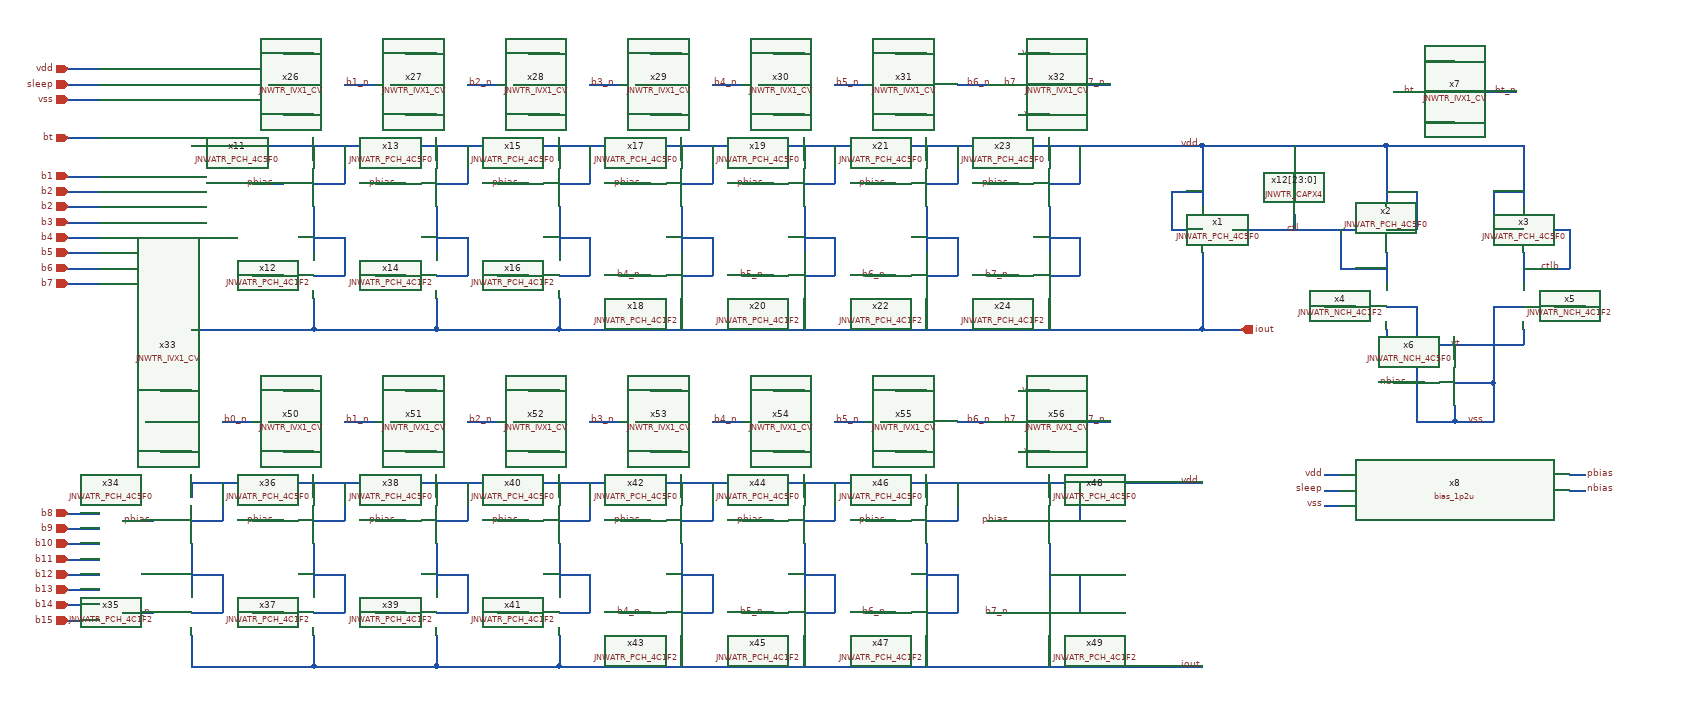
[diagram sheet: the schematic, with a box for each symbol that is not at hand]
v {xschem version=3.4.6 file_version=1.2}
G {}
K {}
V {}
S {}
E {}
N 920 330 960 330 {lab=pbias}
N 1000 280 1000 300 {lab=vdd}
N 1000 360 1000 420 {lab=#net1}
N 1000 480 1000 520 {lab=iout}
N 920 450 960 450 {lab=b4_n}
N 1000 330 1040 330 {lab=vdd}
N 1040 280 1040 330 {lab=vdd}
N 1000 450 1040 450 {lab=#net1}
N 1040 400 1040 450 {lab=#net1}
N 1000 400 1040 400 {lab=#net1}
N 1020 520 1180 520 {lab=iout}
N 1080 330 1120 330 {lab=pbias}
N 1160 280 1160 300 {lab=vdd}
N 1160 360 1160 420 {lab=#net2}
N 1160 480 1160 520 {lab=iout}
N 1080 450 1120 450 {lab=b5_n}
N 1160 330 1200 330 {lab=vdd}
N 1200 280 1200 330 {lab=vdd}
N 1160 450 1200 450 {lab=#net2}
N 1200 400 1200 450 {lab=#net2}
N 1160 400 1200 400 {lab=#net2}
N 1180 520 1340 520 {lab=iout}
N 1240 330 1280 330 {lab=pbias}
N 1320 280 1320 300 {lab=vdd}
N 1320 360 1320 420 {lab=#net3}
N 1320 480 1320 520 {lab=iout}
N 1240 450 1280 450 {lab=b6_n}
N 1320 330 1360 330 {lab=vdd}
N 1360 280 1360 330 {lab=vdd}
N 1320 450 1360 450 {lab=#net3}
N 1360 400 1360 450 {lab=#net3}
N 1320 400 1360 400 {lab=#net3}
N 1340 520 1500 520 {lab=iout}
N 1400 330 1440 330 {lab=pbias}
N 1480 280 1480 300 {lab=vdd}
N 1480 360 1480 420 {lab=#net4}
N 1480 480 1480 520 {lab=iout}
N 1400 450 1440 450 {lab=b7_n}
N 1480 330 1520 330 {lab=vdd}
N 1520 280 1520 330 {lab=vdd}
N 1480 450 1520 450 {lab=#net4}
N 1520 400 1520 450 {lab=#net4}
N 1480 400 1520 400 {lab=#net4}
N 1020 280 1680 280 {lab=vdd}
N 200 340 240 340 {lab=b2}
N 200 360 240 360 {lab=b2}
N 200 380 240 380 {lab=b3}
N 200 400 240 400 {lab=b4}
N 460 200 480 200 {lab=b1}
N 480 160 520 160 {lab=vdd}
N 480 240 520 240 {lab=vss}
N 560 200 600 200 {lab=b1_n}
N 620 200 640 200 {lab=b2}
N 640 160 680 160 {lab=vdd}
N 640 240 680 240 {lab=vss}
N 720 200 760 200 {lab=b2_n}
N 780 200 800 200 {lab=b3}
N 800 160 840 160 {lab=vdd}
N 800 240 840 240 {lab=vss}
N 880 200 920 200 {lab=b3_n}
N 940 200 960 200 {lab=b4}
N 960 160 1000 160 {lab=vdd}
N 960 240 1000 240 {lab=vss}
N 1040 200 1080 200 {lab=b4_n}
N 1840 730 1860 730 {lab=sleep}
N 2160 730 2180 730 {lab=nbias}
N 2160 710 2180 710 {lab=pbias}
N 1840 750 1860 750 {lab=vss}
N 1840 710 1860 710 {lab=vdd}
N 1720 390 1880 390 {lab=ctl}
N 1680 280 1680 360 {lab=vdd}
N 1500 520 1680 520 {lab=iout}
N 1800 370 1800 390 {lab=ctl}
N 1800 280 1800 300 {lab=vdd}
N 1680 280 1920 280 {lab=vdd}
N 1920 280 1920 360 {lab=vdd}
N 1920 390 1960 390 {lab=vdd}
N 1960 340 1960 390 {lab=vdd}
N 1920 340 1960 340 {lab=vdd}
N 1860 390 1860 440 {lab=ctl}
N 1860 440 1920 440 {lab=ctl}
N 1920 420 1920 460 {lab=ctl}
N 2140 390 2160 390 {lab=ctlb}
N 2100 280 2100 360 {lab=vdd}
N 2060 390 2100 390 {lab=vdd}
N 2060 340 2060 390 {lab=vdd}
N 2160 390 2160 440 {lab=ctlb}
N 2100 440 2160 440 {lab=ctlb}
N 2100 420 2100 460 {lab=ctlb}
N 1920 280 2100 280 {lab=vdd}
N 2060 340 2100 340 {lab=vdd}
N 1680 420 1680 520 {lab=iout}
N 2060 490 2100 490 {lab=vss}
N 1920 490 1960 490 {lab=vss}
N 1920 520 1920 540 {lab=vt}
N 2100 520 2100 540 {lab=vt}
N 1840 490 1880 490 {lab=bt}
N 2140 490 2180 490 {lab=bt_n}
N 2010 540 2010 560 {lab=vt}
N 2060 590 2060 640 {lab=vss}
N 1640 390 1680 390 {lab=vdd}
N 1640 340 1640 390 {lab=vdd}
N 1640 340 1680 340 {lab=vdd}
N 2010 620 2010 640 {lab=vss}
N 2010 590 2060 590 {lab=vss}
N 2010 640 2060 640 {lab=vss}
N 1930 590 1970 590 {lab=nbias}
N 1680 520 1730 520 {lab=iout}
N 200 200 240 200 {lab=sleep}
N 200 180 240 180 {lab=vdd}
N 200 220 240 220 {lab=vss}
N 360 520 520 520 {lab=iout}
N 440 330 480 330 {lab=pbias}
N 520 280 520 300 {lab=vdd}
N 520 360 520 420 {lab=#net5}
N 520 480 520 520 {lab=iout}
N 440 450 480 450 {lab=b1_n}
N 520 330 560 330 {lab=vdd}
N 560 280 560 330 {lab=vdd}
N 520 450 560 450 {lab=#net5}
N 560 400 560 450 {lab=#net5}
N 520 400 560 400 {lab=#net5}
N 520 520 680 520 {lab=iout}
N 600 330 640 330 {lab=pbias}
N 680 280 680 300 {lab=vdd}
N 680 360 680 420 {lab=#net6}
N 680 480 680 520 {lab=iout}
N 600 450 640 450 {lab=b2_n}
N 680 330 720 330 {lab=vdd}
N 720 280 720 330 {lab=vdd}
N 680 450 720 450 {lab=#net6}
N 720 400 720 450 {lab=#net6}
N 680 400 720 400 {lab=#net6}
N 680 520 840 520 {lab=iout}
N 760 330 800 330 {lab=pbias}
N 840 280 840 300 {lab=vdd}
N 840 360 840 420 {lab=#net7}
N 840 480 840 520 {lab=iout}
N 760 450 800 450 {lab=b3_n}
N 840 330 880 330 {lab=vdd}
N 880 280 880 330 {lab=vdd}
N 840 450 880 450 {lab=#net7}
N 880 400 880 450 {lab=#net7}
N 840 400 880 400 {lab=#net7}
N 360 280 1020 280 {lab=vdd}
N 840 520 1020 520 {lab=iout}
N 200 420 240 420 {lab=b5}
N 200 440 240 440 {lab=b6}
N 200 460 240 460 {lab=b7}
N 1100 200 1120 200 {lab=b5}
N 1120 160 1160 160 {lab=vdd}
N 1120 240 1160 240 {lab=vss}
N 1200 200 1240 200 {lab=b5_n}
N 1260 200 1280 200 {lab=b6}
N 1280 160 1320 160 {lab=vdd}
N 1280 240 1320 240 {lab=vss}
N 1360 200 1400 200 {lab=b6_n}
N 1420 200 1440 200 {lab=b7}
N 1440 160 1480 160 {lab=vdd}
N 1440 240 1480 240 {lab=vss}
N 1520 200 1560 200 {lab=b7_n}
N 1930 210 1970 210 {lab=bt}
N 1970 170 2010 170 {lab=vdd}
N 1970 250 2010 250 {lab=vss}
N 2050 210 2090 210 {lab=bt_n}
N 200 270 240 270 {lab=bt}
N 200 780 240 780 {lab=b9}
N 200 800 240 800 {lab=b10}
N 200 820 240 820 {lab=b11}
N 200 840 240 840 {lab=b12}
N 200 760 240 760 {lab=b8}
N 200 860 240 860 {lab=b13}
N 200 880 240 880 {lab=b14}
N 200 900 240 900 {lab=b15}
N 1960 490 1960 640 {lab=vss}
N 1960 640 2010 640 {lab=vss}
N 2060 490 2060 590 {lab=vss}
N 1920 540 2100 540 {lab=vt}
N 920 770 960 770 {lab=pbias}
N 1000 720 1000 740 {lab=vdd}
N 1000 800 1000 860 {lab=#net8}
N 1000 920 1000 960 {lab=iout}
N 920 890 960 890 {lab=b4_n}
N 1000 770 1040 770 {lab=vdd}
N 1040 720 1040 770 {lab=vdd}
N 1000 890 1040 890 {lab=#net8}
N 1040 840 1040 890 {lab=#net8}
N 1000 840 1040 840 {lab=#net8}
N 1020 960 1180 960 {lab=iout}
N 1080 770 1120 770 {lab=pbias}
N 1160 720 1160 740 {lab=vdd}
N 1160 800 1160 860 {lab=#net9}
N 1160 920 1160 960 {lab=iout}
N 1080 890 1120 890 {lab=b5_n}
N 1160 770 1200 770 {lab=vdd}
N 1200 720 1200 770 {lab=vdd}
N 1160 890 1200 890 {lab=#net9}
N 1200 840 1200 890 {lab=#net9}
N 1160 840 1200 840 {lab=#net9}
N 1180 960 1340 960 {lab=iout}
N 1240 770 1280 770 {lab=pbias}
N 1320 720 1320 740 {lab=vdd}
N 1320 800 1320 860 {lab=#net10}
N 1320 920 1320 960 {lab=iout}
N 1240 890 1280 890 {lab=b6_n}
N 1320 770 1360 770 {lab=vdd}
N 1360 720 1360 770 {lab=vdd}
N 1320 890 1360 890 {lab=#net10}
N 1360 840 1360 890 {lab=#net10}
N 1320 840 1360 840 {lab=#net10}
N 1340 960 1500 960 {lab=iout}
N 1400 770 1440 770 {lab=pbias}
N 1480 720 1480 740 {lab=vdd}
N 1480 800 1480 860 {lab=#net11}
N 1480 920 1480 960 {lab=iout}
N 1400 890 1440 890 {lab=b7_n}
N 1480 770 1520 770 {lab=vdd}
N 1520 720 1520 770 {lab=vdd}
N 1480 890 1520 890 {lab=#net11}
N 1520 840 1520 890 {lab=#net11}
N 1480 840 1520 840 {lab=#net11}
N 1020 720 1680 720 {lab=vdd}
N 300 640 320 640 {lab=b0}
N 320 600 360 600 {lab=vdd}
N 320 680 360 680 {lab=vss}
N 400 640 440 640 {lab=b0_n}
N 460 640 480 640 {lab=b1}
N 480 600 520 600 {lab=vdd}
N 480 680 520 680 {lab=vss}
N 560 640 600 640 {lab=b1_n}
N 620 640 640 640 {lab=b2}
N 640 600 680 600 {lab=vdd}
N 640 680 680 680 {lab=vss}
N 720 640 760 640 {lab=b2_n}
N 780 640 800 640 {lab=b3}
N 800 600 840 600 {lab=vdd}
N 800 680 840 680 {lab=vss}
N 880 640 920 640 {lab=b3_n}
N 940 640 960 640 {lab=b4}
N 960 600 1000 600 {lab=vdd}
N 960 680 1000 680 {lab=vss}
N 1040 640 1080 640 {lab=b4_n}
N 1500 960 1680 960 {lab=iout}
N 270 770 310 770 {lab=pbias}
N 360 720 360 740 {lab=vdd}
N 360 800 360 860 {lab=#net12}
N 360 920 360 960 {lab=iout}
N 270 890 310 890 {lab=b0_n}
N 360 770 400 770 {lab=vdd}
N 400 720 400 770 {lab=vdd}
N 360 890 400 890 {lab=#net12}
N 400 840 400 890 {lab=#net12}
N 360 840 400 840 {lab=#net12}
N 360 960 520 960 {lab=iout}
N 440 770 480 770 {lab=pbias}
N 520 720 520 740 {lab=vdd}
N 520 800 520 860 {lab=#net13}
N 520 920 520 960 {lab=iout}
N 440 890 480 890 {lab=b1_n}
N 520 770 560 770 {lab=vdd}
N 560 720 560 770 {lab=vdd}
N 520 890 560 890 {lab=#net13}
N 560 840 560 890 {lab=#net13}
N 520 840 560 840 {lab=#net13}
N 520 960 680 960 {lab=iout}
N 600 770 640 770 {lab=pbias}
N 680 720 680 740 {lab=vdd}
N 680 800 680 860 {lab=#net14}
N 680 920 680 960 {lab=iout}
N 600 890 640 890 {lab=b2_n}
N 680 770 720 770 {lab=vdd}
N 720 720 720 770 {lab=vdd}
N 680 890 720 890 {lab=#net14}
N 720 840 720 890 {lab=#net14}
N 680 840 720 840 {lab=#net14}
N 680 960 840 960 {lab=iout}
N 760 770 800 770 {lab=pbias}
N 840 720 840 740 {lab=vdd}
N 840 800 840 860 {lab=#net15}
N 840 920 840 960 {lab=iout}
N 760 890 800 890 {lab=b3_n}
N 840 770 880 770 {lab=vdd}
N 880 720 880 770 {lab=vdd}
N 840 890 880 890 {lab=#net15}
N 880 840 880 890 {lab=#net15}
N 840 840 880 840 {lab=#net15}
N 360 720 1020 720 {lab=vdd}
N 840 960 1020 960 {lab=iout}
N 1100 640 1120 640 {lab=b5}
N 1120 600 1160 600 {lab=vdd}
N 1120 680 1160 680 {lab=vss}
N 1200 640 1240 640 {lab=b5_n}
N 1260 640 1280 640 {lab=b6}
N 1280 600 1320 600 {lab=vdd}
N 1280 680 1320 680 {lab=vss}
N 1360 640 1400 640 {lab=b6_n}
N 1420 640 1440 640 {lab=b7}
N 1440 600 1480 600 {lab=vdd}
N 1440 680 1480 680 {lab=vss}
N 1520 640 1560 640 {lab=b7_n}
N 200 320 240 320 {lab=b1}
C {devices/lab_wire.sym} 1430 450 0 0 {name=p3 sig_type=std_logic lab=b7_n
}
C {devices/lab_wire.sym} 1270 450 0 0 {name=p4 sig_type=std_logic lab=b6_n
}
C {devices/lab_wire.sym} 1110 450 0 0 {name=p5 sig_type=std_logic lab=b5_n
}
C {devices/lab_wire.sym} 950 450 0 0 {name=p6 sig_type=std_logic lab=b4_n
}
C {devices/ipin.sym} 200 180 0 0 {name=p14 lab=vdd}
C {devices/ipin.sym} 200 220 0 0 {name=p15 lab=vss}
C {devices/ipin.sym} 200 340 0 0 {name=p17 lab=b2}
C {devices/ipin.sym} 200 360 0 0 {name=p18 lab=b2}
C {devices/ipin.sym} 200 380 0 0 {name=p19 lab=b3}
C {devices/ipin.sym} 200 400 0 0 {name=p20 lab=b4}
C {devices/lab_wire.sym} 510 240 2 1 {name=p26 sig_type=std_logic lab=vss}
C {devices/lab_wire.sym} 510 160 0 0 {name=p27 sig_type=std_logic lab=vdd}
C {devices/lab_wire.sym} 670 240 2 1 {name=p30 sig_type=std_logic lab=vss}
C {devices/lab_wire.sym} 670 160 0 0 {name=p31 sig_type=std_logic lab=vdd}
C {devices/lab_wire.sym} 830 240 2 1 {name=p34 sig_type=std_logic lab=vss}
C {devices/lab_wire.sym} 830 160 0 0 {name=p35 sig_type=std_logic lab=vdd}
C {devices/lab_wire.sym} 990 240 2 1 {name=p38 sig_type=std_logic lab=vss}
C {devices/lab_wire.sym} 990 160 0 0 {name=p39 sig_type=std_logic lab=vdd}
C {devices/lab_wire.sym} 800 200 0 0 {name=p25 sig_type=std_logic lab=b3}
C {devices/lab_wire.sym} 480 200 0 0 {name=p28 sig_type=std_logic lab=b1}
C {devices/lab_wire.sym} 960 200 0 0 {name=p29 sig_type=std_logic lab=b4}
C {devices/lab_wire.sym} 640 200 0 0 {name=p32 sig_type=std_logic lab=b2}
C {devices/lab_wire.sym} 880 200 0 1 {name=p36 sig_type=std_logic lab=b3_n}
C {devices/lab_wire.sym} 560 200 0 1 {name=p40 sig_type=std_logic lab=b1_n}
C {devices/lab_wire.sym} 1040 200 0 1 {name=p41 sig_type=std_logic lab=b4_n}
C {devices/lab_wire.sym} 720 200 0 1 {name=p45 sig_type=std_logic lab=b2_n}
C {devices/lab_wire.sym} 1110 330 0 0 {name=p9 sig_type=std_logic lab=pbias
}
C {devices/lab_wire.sym} 1270 330 0 0 {name=p8 sig_type=std_logic lab=pbias
}
C {devices/lab_wire.sym} 1430 330 0 0 {name=p10 sig_type=std_logic lab=pbias
}
C {devices/lab_wire.sym} 950 330 0 0 {name=p12 sig_type=std_logic lab=pbias
}
C {devices/ipin.sym} 200 200 0 0 {name=p33 lab=sleep}
C {devices/lab_wire.sym} 2180 710 0 1 {name=p13 sig_type=std_logic lab=pbias
}
C {devices/lab_wire.sym} 2180 730 0 1 {name=p21 sig_type=std_logic lab=nbias
}
C {JNW_TR_SKY130A/JNWTR_CAPX4.sym} 1800 360 0 0 {name=x12[23:0]}
C {devices/lab_wire.sym} 2150 490 0 1 {name=p1 sig_type=std_logic lab=bt_n}
C {devices/lab_wire.sym} 1870 490 0 0 {name=p2 sig_type=std_logic lab=bt}
C {devices/lab_wire.sym} 1950 590 0 0 {name=p11 sig_type=std_logic lab=nbias
}
C {devices/lab_wire.sym} 1810 390 2 1 {name=p42 sig_type=std_logic lab=ctl
}
C {devices/lab_wire.sym} 2120 440 2 0 {name=p43 sig_type=std_logic lab=ctlb
}
C {devices/lab_wire.sym} 2020 540 0 0 {name=p44 sig_type=std_logic lab=vt}
C {devices/lab_wire.sym} 1840 750 0 0 {name=p50 sig_type=std_logic lab=vss
}
C {devices/lab_wire.sym} 1840 710 0 0 {name=p51 sig_type=std_logic lab=vdd
}
C {devices/opin.sym} 1730 520 0 0 {name=p54 lab=iout}
C {devices/lab_wire.sym} 2050 640 0 0 {name=p52 sig_type=std_logic lab=vss
}
C {devices/lab_wire.sym} 1840 730 0 0 {name=p53 sig_type=std_logic lab=sleep
}
C {devices/lab_wire.sym} 790 450 0 0 {name=p55 sig_type=std_logic lab=b3_n
}
C {devices/lab_wire.sym} 630 450 0 0 {name=p56 sig_type=std_logic lab=b2_n
}
C {devices/lab_wire.sym} 470 450 0 0 {name=p57 sig_type=std_logic lab=b1_n
}
C {devices/lab_wire.sym} 470 330 0 0 {name=p59 sig_type=std_logic lab=pbias
}
C {devices/lab_wire.sym} 630 330 0 0 {name=p60 sig_type=std_logic lab=pbias
}
C {devices/lab_wire.sym} 790 330 0 0 {name=p61 sig_type=std_logic lab=pbias
}
C {devices/lab_wire.sym} 1650 280 0 1 {name=p67 sig_type=std_logic lab=vdd
}
C {devices/ipin.sym} 200 420 0 0 {name=p22 lab=b5}
C {devices/ipin.sym} 200 440 0 0 {name=p68 lab=b6}
C {devices/ipin.sym} 200 460 0 0 {name=p69 lab=b7}
C {devices/lab_wire.sym} 1150 240 2 1 {name=p70 sig_type=std_logic lab=vss}
C {devices/lab_wire.sym} 1150 160 0 0 {name=p71 sig_type=std_logic lab=vdd}
C {devices/lab_wire.sym} 1120 200 0 0 {name=p72 sig_type=std_logic lab=b5}
C {devices/lab_wire.sym} 1200 200 0 1 {name=p73 sig_type=std_logic lab=b5_n}
C {devices/lab_wire.sym} 1310 240 2 1 {name=p74 sig_type=std_logic lab=vss}
C {devices/lab_wire.sym} 1310 160 0 0 {name=p75 sig_type=std_logic lab=vdd}
C {devices/lab_wire.sym} 1280 200 0 0 {name=p76 sig_type=std_logic lab=b6}
C {devices/lab_wire.sym} 1370 200 0 1 {name=p77 sig_type=std_logic lab=b6_n}
C {devices/lab_wire.sym} 1470 240 2 1 {name=p78 sig_type=std_logic lab=vss}
C {devices/lab_wire.sym} 1470 160 0 0 {name=p79 sig_type=std_logic lab=vdd}
C {devices/lab_wire.sym} 1440 200 0 0 {name=p80 sig_type=std_logic lab=b7}
C {devices/lab_wire.sym} 1520 200 0 1 {name=p81 sig_type=std_logic lab=b7_n}
C {devices/lab_wire.sym} 2000 250 2 1 {name=p82 sig_type=std_logic lab=vss}
C {devices/lab_wire.sym} 2000 170 0 0 {name=p83 sig_type=std_logic lab=vdd}
C {devices/lab_wire.sym} 1960 210 0 0 {name=p84 sig_type=std_logic lab=bt}
C {devices/lab_wire.sym} 2060 210 0 1 {name=p85 sig_type=std_logic lab=bt_n}
C {devices/ipin.sym} 200 270 0 0 {name=p86 lab=bt}
C {devices/ipin.sym} 200 780 0 0 {name=p139 lab=b9}
C {devices/ipin.sym} 200 800 0 0 {name=p145 lab=b10}
C {devices/ipin.sym} 200 820 0 0 {name=p147 lab=b11}
C {devices/ipin.sym} 200 840 0 0 {name=p165 lab=b12}
C {devices/ipin.sym} 200 760 0 0 {name=p166 lab=b8}
C {devices/ipin.sym} 200 860 0 0 {name=p167 lab=b13}
C {devices/ipin.sym} 200 880 0 0 {name=p168 lab=b14}
C {devices/ipin.sym} 200 900 0 0 {name=p169 lab=b15}
C {JNW_ATR_SKY130A/JNWATR_PCH_4C5F0.sym} 1720 390 0 1 {name=x1 }
C {JNW_ATR_SKY130A/JNWATR_PCH_4C5F0.sym} 1880 390 0 0 {name=x2 }
C {JNW_ATR_SKY130A/JNWATR_PCH_4C5F0.sym} 2140 390 0 1 {name=x3 }
C {JNW_ATR_SKY130A/JNWATR_NCH_4C1F2.sym} 1880 490 0 0 {name=x4 }
C {JNW_ATR_SKY130A/JNWATR_NCH_4C1F2.sym} 2140 490 0 1 {name=x5 }
C {JNW_ATR_SKY130A/JNWATR_NCH_4C5F0.sym} 1970 590 0 0 {name=x6 }
C {JNW_TR_SKY130A/JNWTR_IVX1_CV.sym} 1970 210 0 0 {name=x7 }
C {LELO_TORD_SKY130A/bias_1p2u.sym} 2010 730 0 0 {name=x8}
C {JNW_ATR_SKY130A/JNWATR_PCH_4C5F0.sym} 480 330 0 0 {name=x11 }
C {JNW_ATR_SKY130A/JNWATR_PCH_4C1F2.sym} 480 450 0 0 {name=x12 }
C {JNW_ATR_SKY130A/JNWATR_PCH_4C5F0.sym} 640 330 0 0 {name=x13 }
C {JNW_ATR_SKY130A/JNWATR_PCH_4C1F2.sym} 640 450 0 0 {name=x14 }
C {JNW_ATR_SKY130A/JNWATR_PCH_4C5F0.sym} 800 330 0 0 {name=x15 }
C {JNW_ATR_SKY130A/JNWATR_PCH_4C1F2.sym} 800 450 0 0 {name=x16 }
C {JNW_ATR_SKY130A/JNWATR_PCH_4C5F0.sym} 960 330 0 0 {name=x17 }
C {JNW_ATR_SKY130A/JNWATR_PCH_4C1F2.sym} 960 450 0 0 {name=x18 }
C {JNW_ATR_SKY130A/JNWATR_PCH_4C5F0.sym} 1120 330 0 0 {name=x19 }
C {JNW_ATR_SKY130A/JNWATR_PCH_4C1F2.sym} 1120 450 0 0 {name=x20 }
C {JNW_ATR_SKY130A/JNWATR_PCH_4C5F0.sym} 1280 330 0 0 {name=x21 }
C {JNW_ATR_SKY130A/JNWATR_PCH_4C1F2.sym} 1280 450 0 0 {name=x22 }
C {JNW_ATR_SKY130A/JNWATR_PCH_4C5F0.sym} 1440 330 0 0 {name=x23 }
C {JNW_ATR_SKY130A/JNWATR_PCH_4C1F2.sym} 1440 450 0 0 {name=x24 }
C {JNW_TR_SKY130A/JNWTR_IVX1_CV.sym} 480 200 0 0 {name=x26 }
C {JNW_TR_SKY130A/JNWTR_IVX1_CV.sym} 640 200 0 0 {name=x27 }
C {JNW_TR_SKY130A/JNWTR_IVX1_CV.sym} 800 200 0 0 {name=x28 }
C {JNW_TR_SKY130A/JNWTR_IVX1_CV.sym} 960 200 0 0 {name=x29 }
C {JNW_TR_SKY130A/JNWTR_IVX1_CV.sym} 1120 200 0 0 {name=x30 }
C {JNW_TR_SKY130A/JNWTR_IVX1_CV.sym} 1280 200 0 0 {name=x31 }
C {JNW_TR_SKY130A/JNWTR_IVX1_CV.sym} 1440 200 0 0 {name=x32 }
C {devices/lab_wire.sym} 1430 890 0 0 {name=p46 sig_type=std_logic lab=b7_n
}
C {devices/lab_wire.sym} 1270 890 0 0 {name=p47 sig_type=std_logic lab=b6_n
}
C {devices/lab_wire.sym} 1110 890 0 0 {name=p48 sig_type=std_logic lab=b5_n
}
C {devices/lab_wire.sym} 950 890 0 0 {name=p49 sig_type=std_logic lab=b4_n
}
C {devices/lab_wire.sym} 350 680 2 1 {name=p63 sig_type=std_logic lab=vss}
C {devices/lab_wire.sym} 350 600 0 0 {name=p64 sig_type=std_logic lab=vdd}
C {devices/lab_wire.sym} 510 680 2 1 {name=p65 sig_type=std_logic lab=vss}
C {devices/lab_wire.sym} 510 600 0 0 {name=p66 sig_type=std_logic lab=vdd}
C {devices/lab_wire.sym} 670 680 2 1 {name=p87 sig_type=std_logic lab=vss}
C {devices/lab_wire.sym} 670 600 0 0 {name=p88 sig_type=std_logic lab=vdd}
C {devices/lab_wire.sym} 830 680 2 1 {name=p89 sig_type=std_logic lab=vss}
C {devices/lab_wire.sym} 830 600 0 0 {name=p90 sig_type=std_logic lab=vdd}
C {devices/lab_wire.sym} 990 680 2 1 {name=p91 sig_type=std_logic lab=vss}
C {devices/lab_wire.sym} 990 600 0 0 {name=p92 sig_type=std_logic lab=vdd}
C {devices/lab_wire.sym} 320 640 0 0 {name=p93 sig_type=std_logic lab=b0}
C {devices/lab_wire.sym} 800 640 0 0 {name=p94 sig_type=std_logic lab=b3}
C {devices/lab_wire.sym} 480 640 0 0 {name=p95 sig_type=std_logic lab=b1}
C {devices/lab_wire.sym} 960 640 0 0 {name=p96 sig_type=std_logic lab=b4}
C {devices/lab_wire.sym} 640 640 0 0 {name=p97 sig_type=std_logic lab=b2}
C {devices/lab_wire.sym} 880 640 0 1 {name=p98 sig_type=std_logic lab=b3_n}
C {devices/lab_wire.sym} 400 640 0 1 {name=p99 sig_type=std_logic lab=b0_n}
C {devices/lab_wire.sym} 560 640 0 1 {name=p100 sig_type=std_logic lab=b1_n}
C {devices/lab_wire.sym} 1040 640 0 1 {name=p101 sig_type=std_logic lab=b4_n}
C {devices/lab_wire.sym} 720 640 0 1 {name=p102 sig_type=std_logic lab=b2_n}
C {devices/lab_wire.sym} 1110 770 0 0 {name=p103 sig_type=std_logic lab=pbias
}
C {devices/lab_wire.sym} 1270 770 0 0 {name=p104 sig_type=std_logic lab=pbias
}
C {devices/lab_wire.sym} 1430 770 0 0 {name=p105 sig_type=std_logic lab=pbias
}
C {devices/lab_wire.sym} 950 770 0 0 {name=p106 sig_type=std_logic lab=pbias
}
C {devices/lab_wire.sym} 790 890 0 0 {name=p107 sig_type=std_logic lab=b3_n
}
C {devices/lab_wire.sym} 630 890 0 0 {name=p108 sig_type=std_logic lab=b2_n
}
C {devices/lab_wire.sym} 470 890 0 0 {name=p109 sig_type=std_logic lab=b1_n
}
C {devices/lab_wire.sym} 310 890 0 0 {name=p110 sig_type=std_logic lab=b0_n
}
C {devices/lab_wire.sym} 470 770 0 0 {name=p111 sig_type=std_logic lab=pbias
}
C {devices/lab_wire.sym} 630 770 0 0 {name=p112 sig_type=std_logic lab=pbias
}
C {devices/lab_wire.sym} 790 770 0 0 {name=p113 sig_type=std_logic lab=pbias
}
C {devices/lab_wire.sym} 310 770 0 0 {name=p114 sig_type=std_logic lab=pbias
}
C {devices/lab_wire.sym} 1150 680 2 1 {name=p115 sig_type=std_logic lab=vss}
C {devices/lab_wire.sym} 1150 600 0 0 {name=p116 sig_type=std_logic lab=vdd}
C {devices/lab_wire.sym} 1120 640 0 0 {name=p117 sig_type=std_logic lab=b5}
C {devices/lab_wire.sym} 1200 640 0 1 {name=p118 sig_type=std_logic lab=b5_n}
C {devices/lab_wire.sym} 1310 680 2 1 {name=p119 sig_type=std_logic lab=vss}
C {devices/lab_wire.sym} 1310 600 0 0 {name=p120 sig_type=std_logic lab=vdd}
C {devices/lab_wire.sym} 1280 640 0 0 {name=p121 sig_type=std_logic lab=b6}
C {devices/lab_wire.sym} 1370 640 0 1 {name=p122 sig_type=std_logic lab=b6_n}
C {devices/lab_wire.sym} 1470 680 2 1 {name=p123 sig_type=std_logic lab=vss}
C {devices/lab_wire.sym} 1470 600 0 0 {name=p124 sig_type=std_logic lab=vdd}
C {devices/lab_wire.sym} 1440 640 0 0 {name=p125 sig_type=std_logic lab=b7}
C {devices/lab_wire.sym} 1520 640 0 1 {name=p126 sig_type=std_logic lab=b7_n}
C {JNW_TR_SKY130A/JNWTR_IVX1_CV.sym} 320 640 0 0 {name=x33 }
C {JNW_ATR_SKY130A/JNWATR_PCH_4C5F0.sym} 320 770 0 0 {name=x34 }
C {JNW_ATR_SKY130A/JNWATR_PCH_4C1F2.sym} 320 890 0 0 {name=x35 }
C {JNW_ATR_SKY130A/JNWATR_PCH_4C5F0.sym} 480 770 0 0 {name=x36 }
C {JNW_ATR_SKY130A/JNWATR_PCH_4C1F2.sym} 480 890 0 0 {name=x37 }
C {JNW_ATR_SKY130A/JNWATR_PCH_4C5F0.sym} 640 770 0 0 {name=x38 }
C {JNW_ATR_SKY130A/JNWATR_PCH_4C1F2.sym} 640 890 0 0 {name=x39 }
C {JNW_ATR_SKY130A/JNWATR_PCH_4C5F0.sym} 800 770 0 0 {name=x40 }
C {JNW_ATR_SKY130A/JNWATR_PCH_4C1F2.sym} 800 890 0 0 {name=x41 }
C {JNW_ATR_SKY130A/JNWATR_PCH_4C5F0.sym} 960 770 0 0 {name=x42 }
C {JNW_ATR_SKY130A/JNWATR_PCH_4C1F2.sym} 960 890 0 0 {name=x43 }
C {JNW_ATR_SKY130A/JNWATR_PCH_4C5F0.sym} 1120 770 0 0 {name=x44 }
C {JNW_ATR_SKY130A/JNWATR_PCH_4C1F2.sym} 1120 890 0 0 {name=x45 }
C {JNW_ATR_SKY130A/JNWATR_PCH_4C5F0.sym} 1280 770 0 0 {name=x46 }
C {JNW_ATR_SKY130A/JNWATR_PCH_4C1F2.sym} 1280 890 0 0 {name=x47 }
C {JNW_ATR_SKY130A/JNWATR_PCH_4C5F0.sym} 1440 770 0 0 {name=x48 }
C {JNW_ATR_SKY130A/JNWATR_PCH_4C1F2.sym} 1440 890 0 0 {name=x49 }
C {JNW_TR_SKY130A/JNWTR_IVX1_CV.sym} 480 640 0 0 {name=x50 }
C {JNW_TR_SKY130A/JNWTR_IVX1_CV.sym} 640 640 0 0 {name=x51 }
C {JNW_TR_SKY130A/JNWTR_IVX1_CV.sym} 800 640 0 0 {name=x52 }
C {JNW_TR_SKY130A/JNWTR_IVX1_CV.sym} 960 640 0 0 {name=x53 }
C {JNW_TR_SKY130A/JNWTR_IVX1_CV.sym} 1120 640 0 0 {name=x54 }
C {JNW_TR_SKY130A/JNWTR_IVX1_CV.sym} 1280 640 0 0 {name=x55 }
C {JNW_TR_SKY130A/JNWTR_IVX1_CV.sym} 1440 640 0 0 {name=x56 }
C {devices/lab_wire.sym} 1650 720 0 1 {name=p199 sig_type=std_logic lab=vdd
}
C {devices/lab_wire.sym} 1650 960 0 1 {name=p248 sig_type=std_logic lab=iout
}
C {devices/ipin.sym} 200 320 0 0 {name=p62 lab=b1}
